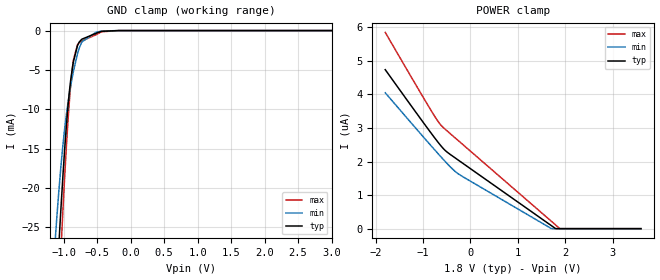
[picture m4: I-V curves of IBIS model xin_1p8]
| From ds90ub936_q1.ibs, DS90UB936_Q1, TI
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|   xin_1p8 Model
[Model]   xin_1p8
Model_type   Input
Vinl = 0.63
Vinh = 1.17
|   typ   min   max
|   (nom PVT)   (fast PVT)   (slow PVT)
C_comp   1.704e-13   1.328e-13   2.119e-13
| Where nom  PVT is Nominal Process, 1.8V, 27C
|   Fast PVT is Strong Process,  1.89V, -40C
|   Slow PVT is Weak Process,   1.71V, 125C
[Voltage Range]   1.8   1.71   1.89
|Junction Temperature
[Temperature Range]   27   125   -40
[Power Clamp Reference]   1.8   1.71   1.89
[GND Clamp Reference]   0   0   0
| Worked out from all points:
|   GND clamp passes 1 mA (typ) near -0.70 V on its own axis
[GND Clamp]
|   Voltage   I(typ)   I(min)   I(max)
-1.8V     -154.6mA   -124.7mA   -182mA
-1.15V    -39.58mA   -29.48mA   -48.51mA
-1.106V   -32.44mA   -24.13mA   -39.94mA
-1.072V   -27.27mA   -20.42mA   -33.67mA
-1.042V   -22.78mA   -17.35mA   -28.17mA
-1.012V   -18.55mA   -14.61mA   -22.93mA
-960.8mV  -12.23mA   -10.75mA   -14.93mA
-866.3mV  -4.545mA   -5.675mA   -4.521mA
-794.5mV  -1.933mA   -2.976mA   -1.8mA
-729mV    -1.098mA   -1.449mA   -1.324mA
-427.9mV  -91.45uA   -59.44uA   -150.4uA
3.6V      0A         0A         0A
[POWER Clamp]
|   Voltage   I(typ)   I(min)   I(max)
-1.8V     4.737uA    4.048uA    5.848uA
-896.6mV  2.971uA    2.574uA    3.672uA
-739.7mV  2.675uA    2.323uA    3.312uA
-628.2mV  2.475uA    2.147uA    3.09uA
-529.2mV  2.323uA    1.994uA    2.956uA
-339.7mV  2.124uA    1.724uA    2.724uA
-180mV    1.965uA    1.564uA    2.529uA
1.707V    90.52nA    0A         221.1nA
1.798V    0A         0A         109.9nA
1.887V    0A         0A         0A
3.6V      0A         0A         0A
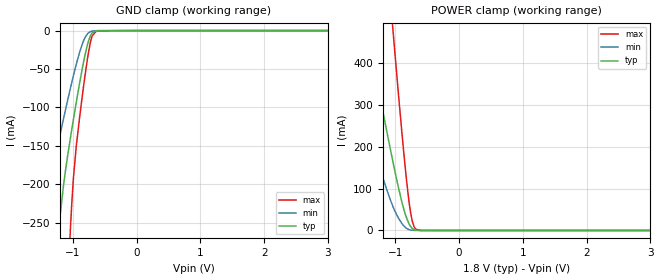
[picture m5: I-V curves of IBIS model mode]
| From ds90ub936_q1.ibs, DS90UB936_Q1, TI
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|   mode Model
[Model]   mode
Model_type   Input
Vinl = 0.63
Vinh = 1.17
|   typ   min   max
|   (nom PVT)   (fast PVT)   (slow PVT)
C_comp   6.288e-13   2.695e-13   1.014e-12
| Where nom  PVT is Nominal Process, 1.8V, 27C
|   Fast PVT is Strong Process,  1.89V, -40C
|   Slow PVT is Weak Process,   1.71V, 125C
[Voltage Range]   1.8   1.71   1.89
|Junction Temperature
[Temperature Range]   27   125   -40
[Power Clamp Reference]   1.8   1.71   1.89
[GND Clamp Reference]   0   0   0
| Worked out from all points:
|   GND clamp passes 1 mA (typ) near -0.65 V on its own axis
|   POWER clamp passes 1 mA (typ) near -0.68 V on its own axis
[GND Clamp]
|   Voltage   I(typ)   I(min)   I(max)
-1.8V     -829.4mA   -449.4mA   -1.962A
-1.561V   -584.5mA   -300.9mA   -1.4A
-1.463V   -486.9mA   -246.6mA   -1.174A
-1.222V   -258.3mA   -143mA     -625.6mA
-1.144V   -199.4mA   -113.5mA   -458.9mA
-1.038V   -139.2mA   -74.74mA   -256.5mA
-996.8mV  -118mA     -60.27mA   -197.7mA
-947.6mV  -93.53mA   -44.05mA   -150.7mA
-829.8mV  -39.55mA   -12.6mA    -70.58mA
-729.5mV  -7.524mA   -1.518mA   -16.81mA
-624.4mV  -228.9uA   -83.28uA   -289.5uA
3.6V      0A         0A         0A
[POWER Clamp]
|   Voltage   I(typ)   I(min)   I(max)
-1.8V     771.3mA    438mA      1.919A
-1.456V   491.1mA    256.1mA    1.26A
-1.404V   449mA      229.1mA    1.161A
-1.208V   293.5mA    131.4mA    792.1mA
-1.067V   185.2mA    68.48mA    531.4mA
-1.033V   159.9mA    55.36mA    469.4mA
-896.6mV  66.8mA     16.24mA    231mA
-810mV    24.03mA    3.665mA    98.5mA
-760.5mV  9.392mA    1.098mA    41.79mA
-707.6mV  2.098mA    260.7uA    9.249mA
-609.3mV  59.75uA    16.29uA    113.9uA
3.6V      0A         0A         0A
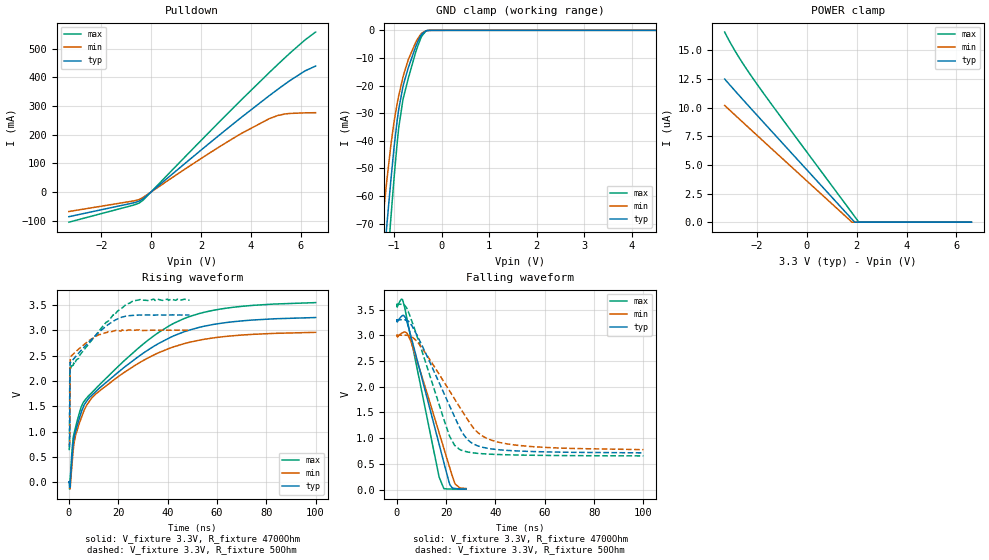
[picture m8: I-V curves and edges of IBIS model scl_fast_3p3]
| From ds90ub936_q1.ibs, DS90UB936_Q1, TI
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|   scl_fast_3p3 Model
[Model]   scl_fast_3p3
Model_type   I/O_open_drain
Polarity   Non-Inverting
Vinl = 0.8
Vinh = 2.0
Vmeas = 1.65
Vref = 3.3
Cref = 400pF
Rref = 4700
|   typ   min   max
|   (nom PVT)   (fast PVT)   (slow PVT)
C_comp   1.660e-13   1.196e-13   2.265e-13
| Where nom  PVT is Nominal Process, 3.3V, 27C
|   Fast PVT is Strong Process,  3.6V, -40C
|   Slow PVT is Weak Process,   3V, 125C
[Voltage Range]   3.3   3   3.6
|Junction Temperature
[Temperature Range]   27   125   -40
[Pullup Reference]   3.3   3   3.6
[Pulldown Reference]   0   0   0
[Power Clamp Reference]   3.3   3   3.6
[GND Clamp Reference]   0   0   0
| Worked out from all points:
|   slope of the pulldown table from 0 to 0.495 V, typ, clamps not added: 13.6 ohm
|   GND clamp passes 1 mA (typ) near -0.39 V on its own axis
|   falling waveform, V_fixture 3.3V, R_fixture 4700Ohm: 20-80 % time 10.7ns typ, 11.4ns min, 9.12ns max; typ from 3.3 V to 0.013 V
|   rising waveform, V_fixture 3.3V, R_fixture 4700Ohm: 20-80 % time 30.3ns typ, 27.2ns min, 31.6ns max; typ from 0.01 V to 3.25 V
|   falling waveform, V_fixture 3.3V, R_fixture 50Ohm: 20-80 % time 14.8ns typ, 17.7ns min, 11.9ns max; typ from 3.3 V to 0.715 V
|   rising waveform, V_fixture 3.3V, R_fixture 50Ohm: 20-80 % time 8.07ns typ, 1.86ns min, 12.2ns max; typ from 0.706 V to 3.3 V
[Pulldown]
|   Voltage   I(typ)   I(min)   I(max)
-3.3V     -86.13mA   -68.1mA    -105.4mA
-702.9mV  -37.8mA    -31.02mA   -45.54mA
-470.4mV  -31.42mA   -25.67mA   -37.93mA
-330mV    -23.9mA    -19.31mA   -29.21mA
1.461V    107.1mA    85.88mA    131.6mA
2.832V    205.4mA    162.8mA    253mA
3.633V    261.4mA    205mA      322.7mA
4.743V    336.5mA    256.1mA    417.2mA
5.082V    358.5mA    267.2mA    445.3mA
5.388V    377.8mA    272.8mA    470.2mA
6.168V    422.5mA    276.4mA    530.4mA
6.6V      439.6mA    277mA      558.4mA
[GND Clamp]
|   Voltage   I(typ)   I(min)   I(max)
-3.3V     -551.9mA   -480.1mA   -622.9mA
-1.337V   -108.8mA   -86.72mA   -131.3mA
-1.226V   -86.04mA   -67.17mA   -105.1mA
-1.152V   -71.05mA   -54.74mA   -87.77mA
-1.068V   -54.85mA   -42.04mA   -68.68mA
-930.6mV  -32.38mA   -26.31mA   -40.4mA
-898.8mV  -28.5mA    -23.56mA   -35.11mA
-812.4mV  -20.47mA   -17.04mA   -25.22mA
-699mV    -13.54mA   -10.6mA    -17.36mA
-513.6mV  -4.647mA   -3.409mA   -6.339mA
-330mV    -193.3uA   -181.3uA   -287.3uA
6.6V      0A         0A         0A
[POWER Clamp]
|   Voltage   I(typ)   I(min)   I(max)
-3.3V     12.49uA    10.18uA    16.58uA
-3.044V   11.85uA    9.664uA    15.54uA
-2.756V   11.14uA    9.084uA    14.48uA
-2.025V   9.382uA    7.62uA     12.1uA
1.809V    255.2nA    0A         809.4nA
1.914V    0A         0A         501.4nA
2.082V    0A         0A         0A
6.6V      0A         0A         0A
[Ramp]
R_load = 4700
|   typ   min   max
dV/dt_r   1.9434/3.02838e-08   1.76758/2.72038e-08   2.12033/3.15834e-08
dV/dt_f   1.96144/1.0664e-08   1.78332/1.13552e-08   2.13783/9.04822e-09
[Falling Waveform]
V_fixture = 3.3V
V_fixture_min = 3V
V_fixture_max = 3.6V
R_fixture = 4700Ohm
|   Time   V(typ)   V(min)   V(max)
0s        3.3V       3V         3.6V
168.6ps   3.268V     2.983V     3.549V
1.967ns   3.37V      3.04V      3.704V
3.145ns   3.365V     3.063V     3.552V
5.744ns   2.978V     2.881V     2.941V
17.17ns   881.5mV    1.105V     244.5mV
19.09ns   526.8mV    800.8mV    19.07mV
21.56ns   90.71mV    411.1mV    12.01mV
23.63ns   23.83mV    110mV      10.58mV
28.13ns   13.22mV    21mV       9.68mV
[Rising Waveform]
V_fixture = 3.3V
V_fixture_min = 3V
V_fixture_max = 3.6V
R_fixture = 4700Ohm
|   Time   V(typ)   V(min)   V(max)
0s        9.536mV    10.71mV    8.512mV
367.6ps   -82.47mV   -38.2mV    -130.5mV
517.3ps   -51.39mV   -124.5mV   39.67mV
1.771ns   763.4mV    632.1mV    890.2mV
2.849ns   1.026V     956mV      1.111V
5.878ns   1.489V     1.381V     1.58V
11.16ns   1.801V     1.753V     1.861V
34.59ns   2.687V     2.514V     2.894V
58.59ns   3.113V     2.847V     3.391V
100ns     3.249V     2.957V     3.542V
[Falling Waveform]
V_fixture = 3.3V
V_fixture_min = 3V
V_fixture_max = 3.6V
R_fixture = 50Ohm
|   Time   V(typ)   V(min)   V(max)
0s        3.3V       3V         3.6V
2.983ns   3.301V     3.001V     3.596V
6.175ns   3.181V     2.973V     3.266V
10.1ns    2.815V     2.762V     2.708V
21.42ns   1.628V     1.917V     1.037V
25.42ns   1.214V     1.61V      783.7mV
28.61ns   972.7mV    1.368V     733.9mV
32.49ns   857mV      1.124V     707.1mV
40.49ns   780.2mV    931mV      684.3mV
100ns     715.1mV    777.8mV    656mV
[Rising Waveform]
V_fixture = 3.3V
V_fixture_min = 3V
V_fixture_max = 3.6V
R_fixture = 50Ohm
|   Time   V(typ)   V(min)   V(max)
0s        705.9mV    757.9mV    653.5mV
230.5ps   710.1mV    745.8mV    695.2mV
309.1ps   819.5mV    782.6mV    1.548V
383ps     1.613V     964mV      2.184V
446.5ps   2.197V     1.579V     2.234V
523.3ps   2.367V     2.165V     2.257V
688.8ps   2.361V     2.477V     2.246V
2.983ns   2.493V     2.583V     2.411V
23.42ns   3.278V     2.994V     3.516V
48.92ns   3.299V     2.999V     3.589V
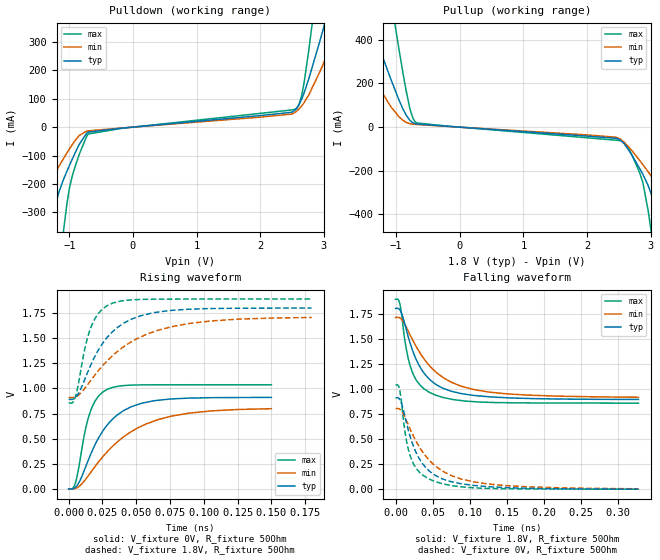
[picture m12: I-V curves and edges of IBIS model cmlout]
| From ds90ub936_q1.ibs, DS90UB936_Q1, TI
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|   cmlout1 Model
[Model]   cmlout
Model_type   Output
Polarity   Non-Inverting
Vmeas = 0.9
Vref = 0
Cref = 2pF
Rref = 70
|   typ   min   max
|   (nom PVT)   (fast PVT)   (slow PVT)
C_comp   6.389e-13   2.780e-13   1.035e-12
| Where nom  PVT is Nominal Process, 1.8V, 27C
|   Fast PVT is Strong Process,  1.89V, -40C
|   Slow PVT is Weak Process,   1.71V, 125C
[Voltage Range]   1.8   1.71   1.89
|Junction Temperature
[Temperature Range]   27   125   -40
[Pullup Reference]   1.8   1.71   1.89
[Pulldown Reference]   0   0   0
[Power Clamp Reference]   1.8   1.71   1.89
[GND Clamp Reference]   0   0   0
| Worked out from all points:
|   slope of the pulldown table from 0 to 0.27 V, typ, clamps not added: 49.1 ohm
|   slope of the pullup table from 0 to 0.27 V, typ, clamps not added: 48.8 ohm
|   falling waveform, V_fixture 1.8V, R_fixture 50Ohm: 20-80 % time 35.4ps typ, 54.4ps min, 21.1ps max; typ from 1.8 V to 0.895 V
|   rising waveform, V_fixture 0V, R_fixture 50Ohm: 20-80 % time 23.8ps typ, 40ps min, 10.4ps max; typ from 0 V to 0.91 V
|   rising waveform, V_fixture 1.8V, R_fixture 50Ohm: 20-80 % time 25.9ps typ, 43.7ps min, 11.6ps max; typ from 0.892 V to 1.8 V
|   falling waveform, V_fixture 0V, R_fixture 50Ohm: 20-80 % time 32.8ps typ, 50.5ps min, 19.4ps max; typ from 0.911 V to 0.003 V
[Pulldown]
|   Voltage   I(typ)   I(min)   I(max)
-1.8V     -847.6mA   -471.7mA   -1.971A
-1.41V    -451.8mA   -239.9mA   -1.064A
-1.269V   -317.2mA   -179.9mA   -744.9mA
-1.086V   -181.3mA   -108.8mA   -356.7mA
-949.5mV  -111mA     -60.46mA   -169mA
-729.5mV  -22.27mA   -14.33mA   -34.04mA
2.502V    52.87mA    46.56mA    60.65mA
2.613V    79.84mA    64.25mA    80.83mA
2.766V    171.3mA    114.1mA    272.1mA
2.933V    298mA      191.7mA    567.5mA
3.207V    521mA      335.9mA    1.087A
3.6V      849mA      551.6mA    1.849A
[Pullup]
|   Voltage   I(typ)   I(min)   I(max)
-1.8V     811.3mA    471.2mA    1.976A
-1.369V   450.7mA    236.1mA    1.136A
-1.077V   215mA      91.56mA    578.4mA
-954mV    123.7mA    47.05mA    354.3mA
-844.2mV  55.93mA    22.27mA    169.1mA
-677.3mV  14.59mA    12.11mA    19.19mA
2.46V     -51.33mA   -46.33mA   -59.89mA
2.723V    -136.6mA   -113.9mA   -138.3mA
2.975V    -278.2mA   -210.3mA   -409.6mA
3.08V     -367.5mA   -253.6mA   -625.6mA
3.29V     -571.5mA   -365.5mA   -1.095A
3.6V      -886.4mA   -561.6mA   -1.811A
[Ramp]
R_load = 50
|   typ   min   max
dV/dt_r   0.546351/2.38441e-11   0.48204/4.06607e-11   0.62238/1.04745e-11
dV/dt_f   0.544765/3.57859e-11   0.47988/5.56984e-11   0.620843/2.13489e-11
[Falling Waveform]
V_fixture = 1.8V
V_fixture_min = 1.71V
V_fixture_max = 1.89V
R_fixture = 50Ohm
|   Time   V(typ)   V(min)   V(max)
0s        1.8V       1.71V      1.89V
3.173ps   1.802V     1.712V     1.891V
5.952ps   1.785V     1.705V     1.84V
14.24ps   1.597V     1.617V     1.407V
22.12ps   1.399V     1.5V       1.176V
35.8ps    1.184V     1.326V     1.019V
53.49ps   1.049V     1.175V     939.6mV
88.77ps   953.4mV    1.027V     884mV
125.8ps   922mV      968.8mV    866.8mV
327.4ps   895.4mV    917.2mV    858.8mV
[Rising Waveform]
V_fixture = 0V
V_fixture_min = 0V
V_fixture_max = 0V
R_fixture = 50Ohm
|   Time   V(typ)   V(min)   V(max)
0s        61.91uV    112.7uV    102.3uV
5.027ps   15.77mV    4.797mV    61.38mV
13.04ps   235.6mV    104.1mV    629.1mV
17.37ps   377.5mV    183.5mV    815.9mV
22.12ps   507mV      268mV      923.8mV
28.55ps   635.7mV    369.5mV    990.8mV
46.4ps    817.8mV    570mV      1.032V
65.93ps   881.1mV    688.2mV    1.036V
105.5ps   907.6mV    776mV      1.036V
150.1ps   909.7mV    797.9mV    1.036V
[Rising Waveform]
V_fixture = 1.8V
V_fixture_min = 1.71V
V_fixture_max = 1.89V
R_fixture = 50Ohm
|   Time   V(typ)   V(min)   V(max)
0s        891.9mV    910mV      855.1mV
5.027ps   909.3mV    915.7mV    917.1mV
11.93ps   1.09V      1V         1.392V
17.37ps   1.262V     1.098V     1.637V
25.06ps   1.446V     1.224V     1.79V
32.92ps   1.569V     1.33V      1.85V
53.61ps   1.724V     1.513V     1.885V
76.15ps   1.776V     1.614V     1.888V
105.5ps   1.794V     1.671V     1.889V
179.9ps   1.799V     1.706V     1.889V
[Falling Waveform]
V_fixture = 0V
V_fixture_min = 0V
V_fixture_max = 0V
R_fixture = 50Ohm
|   Time   V(typ)   V(min)   V(max)
0s        910.9mV    803.8mV    1.038V
3.173ps   912.5mV    805.7mV    1.039V
5.952ps   891.8mV    797.2mV    975.4mV
13.04ps   714.6mV    713mV      557.6mV
19.62ps   527.7mV    601.9mV    337.2mV
31.55ps   312mV      430.5mV    177.9mV
45.12ps   186.4mV    293.7mV    104.3mV
76.15ps   75.48mV    136mV      38.29mV
125.8ps   28.03mV    53.73mV    10.83mV
327.4ps   3.294mV    6.782mV    3.611mV
